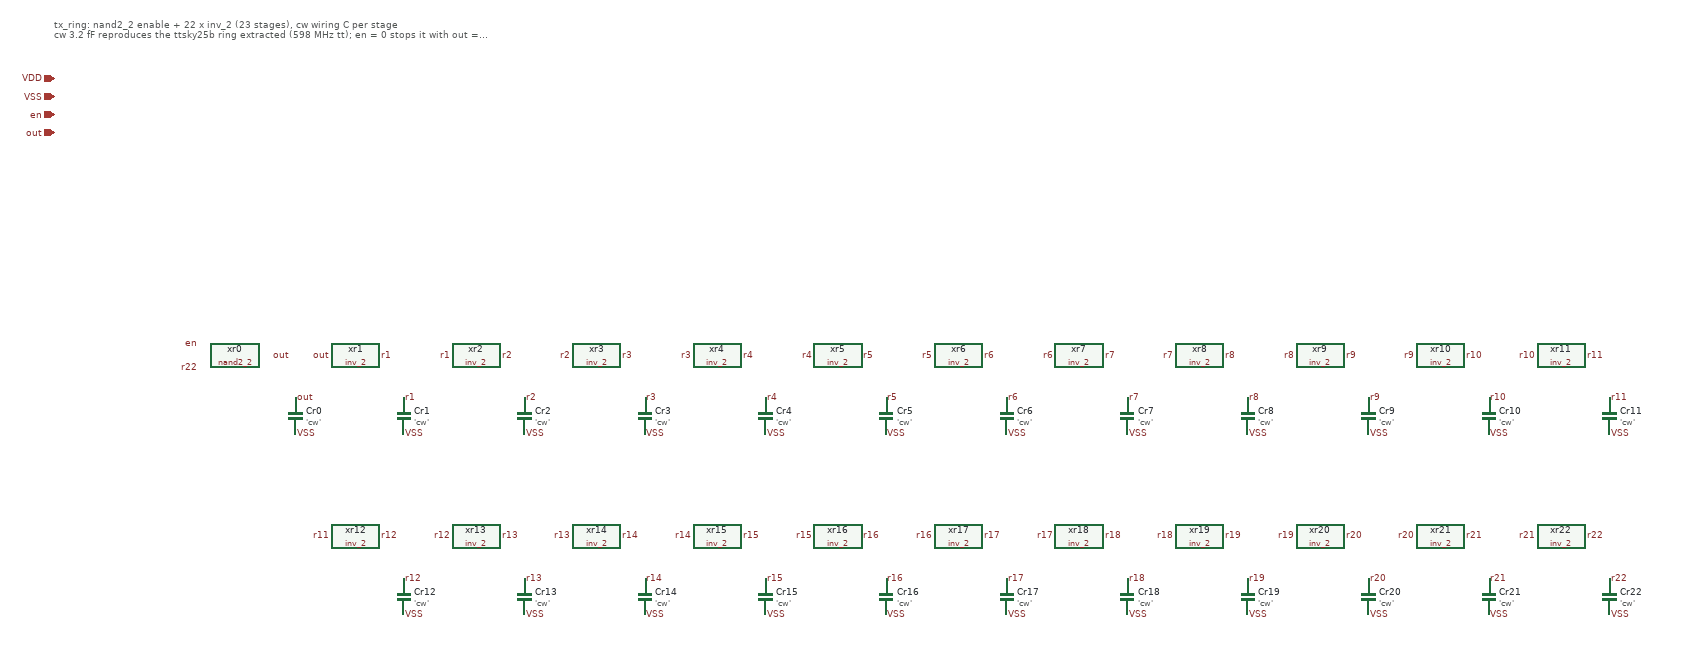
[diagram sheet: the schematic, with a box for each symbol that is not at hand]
v {xschem version=3.4.5 file_version=1.2
}
G {}
K {}
V {}
S {}
E {}
T {tx_ring: nand2_2 enable + 22 x inv_2 (23 stages), cw wiring C per stage
cw 3.2 fF reproduces the ttsky25b ring extracted (598 MHz tt); en = 0 stops it with out = 1} -700 -560 0 0 0.4 0.4 {}
C {devices/iopin.sym} -700 -460 0 0 {name=p1
lab=VDD}
C {devices/iopin.sym} -700 -430 0 0 {name=p2
lab=VSS}
C {devices/iopin.sym} -700 -400 0 0 {name=p3
lab=en}
C {devices/iopin.sym} -700 -370 0 0 {name=p4
lab=out}
C {sky130_stdcells/nand2_2.sym} -400 0 0 0 {name=xr0
VGND=VSS
VNB=VSS
VPB=VDD
VPWR=VDD
prefix=sky130_fd_sc_hd__}
C {devices/lab_pin.sym} -460 -20 0 0 {name=p5
sig_type=std_logic
lab=en}
C {devices/lab_pin.sym} -460 20 0 0 {name=p6
sig_type=std_logic
lab=r22}
C {devices/lab_pin.sym} -340 0 0 1 {name=p7
sig_type=std_logic
lab=out}
C {devices/capa.sym} -300 100 0 0 {name=Cr0
value='cw'
m=1}
C {devices/lab_pin.sym} -300 70 0 1 {name=p8
sig_type=std_logic
lab=out}
C {devices/lab_pin.sym} -300 130 0 1 {name=p9
sig_type=std_logic
lab=VSS}
C {sky130_stdcells/inv_2.sym} -200 0 0 0 {name=xr1
VGND=VSS
VNB=VSS
VPB=VDD
VPWR=VDD
prefix=sky130_fd_sc_hd__}
C {devices/lab_pin.sym} -240 0 0 0 {name=p10
sig_type=std_logic
lab=out}
C {devices/lab_pin.sym} -160 0 0 1 {name=p11
sig_type=std_logic
lab=r1}
C {devices/capa.sym} -120 100 0 0 {name=Cr1
value='cw'
m=1}
C {devices/lab_pin.sym} -120 70 0 1 {name=p12
sig_type=std_logic
lab=r1}
C {devices/lab_pin.sym} -120 130 0 1 {name=p13
sig_type=std_logic
lab=VSS}
C {sky130_stdcells/inv_2.sym} 0 0 0 0 {name=xr2
VGND=VSS
VNB=VSS
VPB=VDD
VPWR=VDD
prefix=sky130_fd_sc_hd__}
C {devices/lab_pin.sym} -40 0 0 0 {name=p14
sig_type=std_logic
lab=r1}
C {devices/lab_pin.sym} 40 0 0 1 {name=p15
sig_type=std_logic
lab=r2}
C {devices/capa.sym} 80 100 0 0 {name=Cr2
value='cw'
m=1}
C {devices/lab_pin.sym} 80 70 0 1 {name=p16
sig_type=std_logic
lab=r2}
C {devices/lab_pin.sym} 80 130 0 1 {name=p17
sig_type=std_logic
lab=VSS}
C {sky130_stdcells/inv_2.sym} 200 0 0 0 {name=xr3
VGND=VSS
VNB=VSS
VPB=VDD
VPWR=VDD
prefix=sky130_fd_sc_hd__}
C {devices/lab_pin.sym} 160 0 0 0 {name=p18
sig_type=std_logic
lab=r2}
C {devices/lab_pin.sym} 240 0 0 1 {name=p19
sig_type=std_logic
lab=r3}
C {devices/capa.sym} 280 100 0 0 {name=Cr3
value='cw'
m=1}
C {devices/lab_pin.sym} 280 70 0 1 {name=p20
sig_type=std_logic
lab=r3}
C {devices/lab_pin.sym} 280 130 0 1 {name=p21
sig_type=std_logic
lab=VSS}
C {sky130_stdcells/inv_2.sym} 400 0 0 0 {name=xr4
VGND=VSS
VNB=VSS
VPB=VDD
VPWR=VDD
prefix=sky130_fd_sc_hd__}
C {devices/lab_pin.sym} 360 0 0 0 {name=p22
sig_type=std_logic
lab=r3}
C {devices/lab_pin.sym} 440 0 0 1 {name=p23
sig_type=std_logic
lab=r4}
C {devices/capa.sym} 480 100 0 0 {name=Cr4
value='cw'
m=1}
C {devices/lab_pin.sym} 480 70 0 1 {name=p24
sig_type=std_logic
lab=r4}
C {devices/lab_pin.sym} 480 130 0 1 {name=p25
sig_type=std_logic
lab=VSS}
C {sky130_stdcells/inv_2.sym} 600 0 0 0 {name=xr5
VGND=VSS
VNB=VSS
VPB=VDD
VPWR=VDD
prefix=sky130_fd_sc_hd__}
C {devices/lab_pin.sym} 560 0 0 0 {name=p26
sig_type=std_logic
lab=r4}
C {devices/lab_pin.sym} 640 0 0 1 {name=p27
sig_type=std_logic
lab=r5}
C {devices/capa.sym} 680 100 0 0 {name=Cr5
value='cw'
m=1}
C {devices/lab_pin.sym} 680 70 0 1 {name=p28
sig_type=std_logic
lab=r5}
C {devices/lab_pin.sym} 680 130 0 1 {name=p29
sig_type=std_logic
lab=VSS}
C {sky130_stdcells/inv_2.sym} 800 0 0 0 {name=xr6
VGND=VSS
VNB=VSS
VPB=VDD
VPWR=VDD
prefix=sky130_fd_sc_hd__}
C {devices/lab_pin.sym} 760 0 0 0 {name=p30
sig_type=std_logic
lab=r5}
C {devices/lab_pin.sym} 840 0 0 1 {name=p31
sig_type=std_logic
lab=r6}
C {devices/capa.sym} 880 100 0 0 {name=Cr6
value='cw'
m=1}
C {devices/lab_pin.sym} 880 70 0 1 {name=p32
sig_type=std_logic
lab=r6}
C {devices/lab_pin.sym} 880 130 0 1 {name=p33
sig_type=std_logic
lab=VSS}
C {sky130_stdcells/inv_2.sym} 1000 0 0 0 {name=xr7
VGND=VSS
VNB=VSS
VPB=VDD
VPWR=VDD
prefix=sky130_fd_sc_hd__}
C {devices/lab_pin.sym} 960 0 0 0 {name=p34
sig_type=std_logic
lab=r6}
C {devices/lab_pin.sym} 1040 0 0 1 {name=p35
sig_type=std_logic
lab=r7}
C {devices/capa.sym} 1080 100 0 0 {name=Cr7
value='cw'
m=1}
C {devices/lab_pin.sym} 1080 70 0 1 {name=p36
sig_type=std_logic
lab=r7}
C {devices/lab_pin.sym} 1080 130 0 1 {name=p37
sig_type=std_logic
lab=VSS}
C {sky130_stdcells/inv_2.sym} 1200 0 0 0 {name=xr8
VGND=VSS
VNB=VSS
VPB=VDD
VPWR=VDD
prefix=sky130_fd_sc_hd__}
C {devices/lab_pin.sym} 1160 0 0 0 {name=p38
sig_type=std_logic
lab=r7}
C {devices/lab_pin.sym} 1240 0 0 1 {name=p39
sig_type=std_logic
lab=r8}
C {devices/capa.sym} 1280 100 0 0 {name=Cr8
value='cw'
m=1}
C {devices/lab_pin.sym} 1280 70 0 1 {name=p40
sig_type=std_logic
lab=r8}
C {devices/lab_pin.sym} 1280 130 0 1 {name=p41
sig_type=std_logic
lab=VSS}
C {sky130_stdcells/inv_2.sym} 1400 0 0 0 {name=xr9
VGND=VSS
VNB=VSS
VPB=VDD
VPWR=VDD
prefix=sky130_fd_sc_hd__}
C {devices/lab_pin.sym} 1360 0 0 0 {name=p42
sig_type=std_logic
lab=r8}
C {devices/lab_pin.sym} 1440 0 0 1 {name=p43
sig_type=std_logic
lab=r9}
C {devices/capa.sym} 1480 100 0 0 {name=Cr9
value='cw'
m=1}
C {devices/lab_pin.sym} 1480 70 0 1 {name=p44
sig_type=std_logic
lab=r9}
C {devices/lab_pin.sym} 1480 130 0 1 {name=p45
sig_type=std_logic
lab=VSS}
C {sky130_stdcells/inv_2.sym} 1600 0 0 0 {name=xr10
VGND=VSS
VNB=VSS
VPB=VDD
VPWR=VDD
prefix=sky130_fd_sc_hd__}
C {devices/lab_pin.sym} 1560 0 0 0 {name=p46
sig_type=std_logic
lab=r9}
C {devices/lab_pin.sym} 1640 0 0 1 {name=p47
sig_type=std_logic
lab=r10}
C {devices/capa.sym} 1680 100 0 0 {name=Cr10
value='cw'
m=1}
C {devices/lab_pin.sym} 1680 70 0 1 {name=p48
sig_type=std_logic
lab=r10}
C {devices/lab_pin.sym} 1680 130 0 1 {name=p49
sig_type=std_logic
lab=VSS}
C {sky130_stdcells/inv_2.sym} 1800 0 0 0 {name=xr11
VGND=VSS
VNB=VSS
VPB=VDD
VPWR=VDD
prefix=sky130_fd_sc_hd__}
C {devices/lab_pin.sym} 1760 0 0 0 {name=p50
sig_type=std_logic
lab=r10}
C {devices/lab_pin.sym} 1840 0 0 1 {name=p51
sig_type=std_logic
lab=r11}
C {devices/capa.sym} 1880 100 0 0 {name=Cr11
value='cw'
m=1}
C {devices/lab_pin.sym} 1880 70 0 1 {name=p52
sig_type=std_logic
lab=r11}
C {devices/lab_pin.sym} 1880 130 0 1 {name=p53
sig_type=std_logic
lab=VSS}
C {sky130_stdcells/inv_2.sym} -200 300 0 0 {name=xr12
VGND=VSS
VNB=VSS
VPB=VDD
VPWR=VDD
prefix=sky130_fd_sc_hd__}
C {devices/lab_pin.sym} -240 300 0 0 {name=p54
sig_type=std_logic
lab=r11}
C {devices/lab_pin.sym} -160 300 0 1 {name=p55
sig_type=std_logic
lab=r12}
C {devices/capa.sym} -120 400 0 0 {name=Cr12
value='cw'
m=1}
C {devices/lab_pin.sym} -120 370 0 1 {name=p56
sig_type=std_logic
lab=r12}
C {devices/lab_pin.sym} -120 430 0 1 {name=p57
sig_type=std_logic
lab=VSS}
C {sky130_stdcells/inv_2.sym} 0 300 0 0 {name=xr13
VGND=VSS
VNB=VSS
VPB=VDD
VPWR=VDD
prefix=sky130_fd_sc_hd__}
C {devices/lab_pin.sym} -40 300 0 0 {name=p58
sig_type=std_logic
lab=r12}
C {devices/lab_pin.sym} 40 300 0 1 {name=p59
sig_type=std_logic
lab=r13}
C {devices/capa.sym} 80 400 0 0 {name=Cr13
value='cw'
m=1}
C {devices/lab_pin.sym} 80 370 0 1 {name=p60
sig_type=std_logic
lab=r13}
C {devices/lab_pin.sym} 80 430 0 1 {name=p61
sig_type=std_logic
lab=VSS}
C {sky130_stdcells/inv_2.sym} 200 300 0 0 {name=xr14
VGND=VSS
VNB=VSS
VPB=VDD
VPWR=VDD
prefix=sky130_fd_sc_hd__}
C {devices/lab_pin.sym} 160 300 0 0 {name=p62
sig_type=std_logic
lab=r13}
C {devices/lab_pin.sym} 240 300 0 1 {name=p63
sig_type=std_logic
lab=r14}
C {devices/capa.sym} 280 400 0 0 {name=Cr14
value='cw'
m=1}
C {devices/lab_pin.sym} 280 370 0 1 {name=p64
sig_type=std_logic
lab=r14}
C {devices/lab_pin.sym} 280 430 0 1 {name=p65
sig_type=std_logic
lab=VSS}
C {sky130_stdcells/inv_2.sym} 400 300 0 0 {name=xr15
VGND=VSS
VNB=VSS
VPB=VDD
VPWR=VDD
prefix=sky130_fd_sc_hd__}
C {devices/lab_pin.sym} 360 300 0 0 {name=p66
sig_type=std_logic
lab=r14}
C {devices/lab_pin.sym} 440 300 0 1 {name=p67
sig_type=std_logic
lab=r15}
C {devices/capa.sym} 480 400 0 0 {name=Cr15
value='cw'
m=1}
C {devices/lab_pin.sym} 480 370 0 1 {name=p68
sig_type=std_logic
lab=r15}
C {devices/lab_pin.sym} 480 430 0 1 {name=p69
sig_type=std_logic
lab=VSS}
C {sky130_stdcells/inv_2.sym} 600 300 0 0 {name=xr16
VGND=VSS
VNB=VSS
VPB=VDD
VPWR=VDD
prefix=sky130_fd_sc_hd__}
C {devices/lab_pin.sym} 560 300 0 0 {name=p70
sig_type=std_logic
lab=r15}
C {devices/lab_pin.sym} 640 300 0 1 {name=p71
sig_type=std_logic
lab=r16}
C {devices/capa.sym} 680 400 0 0 {name=Cr16
value='cw'
m=1}
C {devices/lab_pin.sym} 680 370 0 1 {name=p72
sig_type=std_logic
lab=r16}
C {devices/lab_pin.sym} 680 430 0 1 {name=p73
sig_type=std_logic
lab=VSS}
C {sky130_stdcells/inv_2.sym} 800 300 0 0 {name=xr17
VGND=VSS
VNB=VSS
VPB=VDD
VPWR=VDD
prefix=sky130_fd_sc_hd__}
C {devices/lab_pin.sym} 760 300 0 0 {name=p74
sig_type=std_logic
lab=r16}
C {devices/lab_pin.sym} 840 300 0 1 {name=p75
sig_type=std_logic
lab=r17}
C {devices/capa.sym} 880 400 0 0 {name=Cr17
value='cw'
m=1}
C {devices/lab_pin.sym} 880 370 0 1 {name=p76
sig_type=std_logic
lab=r17}
C {devices/lab_pin.sym} 880 430 0 1 {name=p77
sig_type=std_logic
lab=VSS}
C {sky130_stdcells/inv_2.sym} 1000 300 0 0 {name=xr18
VGND=VSS
VNB=VSS
VPB=VDD
VPWR=VDD
prefix=sky130_fd_sc_hd__}
C {devices/lab_pin.sym} 960 300 0 0 {name=p78
sig_type=std_logic
lab=r17}
C {devices/lab_pin.sym} 1040 300 0 1 {name=p79
sig_type=std_logic
lab=r18}
C {devices/capa.sym} 1080 400 0 0 {name=Cr18
value='cw'
m=1}
C {devices/lab_pin.sym} 1080 370 0 1 {name=p80
sig_type=std_logic
lab=r18}
C {devices/lab_pin.sym} 1080 430 0 1 {name=p81
sig_type=std_logic
lab=VSS}
C {sky130_stdcells/inv_2.sym} 1200 300 0 0 {name=xr19
VGND=VSS
VNB=VSS
VPB=VDD
VPWR=VDD
prefix=sky130_fd_sc_hd__}
C {devices/lab_pin.sym} 1160 300 0 0 {name=p82
sig_type=std_logic
lab=r18}
C {devices/lab_pin.sym} 1240 300 0 1 {name=p83
sig_type=std_logic
lab=r19}
C {devices/capa.sym} 1280 400 0 0 {name=Cr19
value='cw'
m=1}
C {devices/lab_pin.sym} 1280 370 0 1 {name=p84
sig_type=std_logic
lab=r19}
C {devices/lab_pin.sym} 1280 430 0 1 {name=p85
sig_type=std_logic
lab=VSS}
C {sky130_stdcells/inv_2.sym} 1400 300 0 0 {name=xr20
VGND=VSS
VNB=VSS
VPB=VDD
VPWR=VDD
prefix=sky130_fd_sc_hd__}
C {devices/lab_pin.sym} 1360 300 0 0 {name=p86
sig_type=std_logic
lab=r19}
C {devices/lab_pin.sym} 1440 300 0 1 {name=p87
sig_type=std_logic
lab=r20}
C {devices/capa.sym} 1480 400 0 0 {name=Cr20
value='cw'
m=1}
C {devices/lab_pin.sym} 1480 370 0 1 {name=p88
sig_type=std_logic
lab=r20}
C {devices/lab_pin.sym} 1480 430 0 1 {name=p89
sig_type=std_logic
lab=VSS}
C {sky130_stdcells/inv_2.sym} 1600 300 0 0 {name=xr21
VGND=VSS
VNB=VSS
VPB=VDD
VPWR=VDD
prefix=sky130_fd_sc_hd__}
C {devices/lab_pin.sym} 1560 300 0 0 {name=p90
sig_type=std_logic
lab=r20}
C {devices/lab_pin.sym} 1640 300 0 1 {name=p91
sig_type=std_logic
lab=r21}
C {devices/capa.sym} 1680 400 0 0 {name=Cr21
value='cw'
m=1}
C {devices/lab_pin.sym} 1680 370 0 1 {name=p92
sig_type=std_logic
lab=r21}
C {devices/lab_pin.sym} 1680 430 0 1 {name=p93
sig_type=std_logic
lab=VSS}
C {sky130_stdcells/inv_2.sym} 1800 300 0 0 {name=xr22
VGND=VSS
VNB=VSS
VPB=VDD
VPWR=VDD
prefix=sky130_fd_sc_hd__}
C {devices/lab_pin.sym} 1760 300 0 0 {name=p94
sig_type=std_logic
lab=r21}
C {devices/lab_pin.sym} 1840 300 0 1 {name=p95
sig_type=std_logic
lab=r22}
C {devices/capa.sym} 1880 400 0 0 {name=Cr22
value='cw'
m=1}
C {devices/lab_pin.sym} 1880 370 0 1 {name=p96
sig_type=std_logic
lab=r22}
C {devices/lab_pin.sym} 1880 430 0 1 {name=p97
sig_type=std_logic
lab=VSS}
